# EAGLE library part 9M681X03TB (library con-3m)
CONNECTOR PCMCIA-CompactFlash

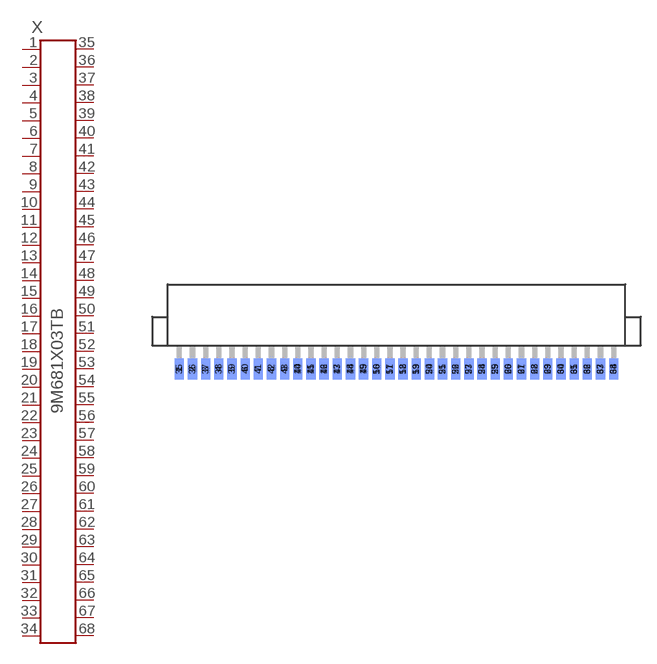
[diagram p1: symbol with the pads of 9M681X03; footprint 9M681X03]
Designator prefix X

## 9M681X03TB (OC_FARNELL: unknown; OC_NEWARK: unknown)  [9M681X03]
1  1  pas
2  2  pas
3  3  pas
4  4  pas
5  5  pas
6  6  pas
7  7  pas
8  8  pas
9  9  pas
10  10  pas
11  11  pas
12  12  pas
13  13  pas
14  14  pas
15  15  pas
16  16  pas
17  17  pas
18  18  pas
19  19  pas
20  20  pas
21  21  pas
22  22  pas
23  23  pas
24  24  pas
25  25  pas
26  26  pas
27  27  pas
28  28  pas
29  29  pas
30  30  pas
31  31  pas
32  32  pas
33  33  pas
34  34  pas
35  35  pas
36  36  pas
37  37  pas
38  38  pas
39  39  pas
40  40  pas
41  41  pas
42  42  pas
43  43  pas
44  44  pas
45  45  pas
46  46  pas
47  47  pas
48  48  pas
49  49  pas
50  50  pas
51  51  pas
52  52  pas
53  53  pas
54  54  pas
55  55  pas
56  56  pas
57  57  pas
58  58  pas
59  59  pas
60  60  pas
61  61  pas
62  62  pas
63  63  pas
64  64  pas
65  65  pas
66  66  pas
67  67  pas
68  68  pas

## Footprint 9M681X03 (pad centres in mm)
CONNECTOR PCMCIA-CompactFlash
smd 0.89 x 2.03: 1 -20.955,-3.29; 2 -19.685,-3.29; 3 -18.415,-3.29; 4 -17.145,-3.29; 5 -15.875,-3.29; 6 -14.605,-3.29; 7 -13.335,-3.29; 8 -12.065,-3.29; 9 -10.795,-3.29; 10 -9.525,-3.29; 11 -8.255,-3.29; 12 -6.985,-3.29; 13 -5.715,-3.29; 14 -4.445,-3.29; 15 -3.175,-3.29; 16 -1.905,-3.29; 17 -0.635,-3.29; 18 0.635,-3.29; 19 1.905,-3.29; 20 3.175,-3.29; 21 4.445,-3.29; 22 5.715,-3.29; 23 6.985,-3.29; 24 8.255,-3.29; 25 9.525,-3.29; 26 10.795,-3.29; 27 12.065,-3.29; 28 13.335,-3.29; 29 14.605,-3.29; 30 15.875,-3.29; 31 17.145,-3.29; 32 18.415,-3.29; 33 19.685,-3.29; 34 20.955,-3.29
smd 0.89 x 2.03 bottom: 35 -20.955,-3.29; 36 -19.685,-3.29; 37 -18.415,-3.29; 38 -17.145,-3.29; 39 -15.875,-3.29; 40 -14.605,-3.29; 41 -13.335,-3.29; 42 -12.065,-3.29; 43 -10.795,-3.29; 44 -9.525,-3.29; 45 -8.255,-3.29; 46 -6.985,-3.29; 47 -5.715,-3.29; 48 -4.445,-3.29; 49 -3.175,-3.29; 50 -1.905,-3.29; 51 -0.635,-3.29; 52 0.635,-3.29; 53 1.905,-3.29; 54 3.175,-3.29; 55 4.445,-3.29; 56 5.715,-3.29; 57 6.985,-3.29; 58 8.255,-3.29; 59 9.525,-3.29; 60 10.795,-3.29; 61 12.065,-3.29; 62 13.335,-3.29; 63 14.605,-3.29; 64 15.875,-3.29; 65 17.145,-3.29; 66 18.415,-3.29; 67 19.685,-3.29; 68 20.955,-3.29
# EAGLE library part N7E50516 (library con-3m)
CONNECTOR PCMCIA-CompactFlash

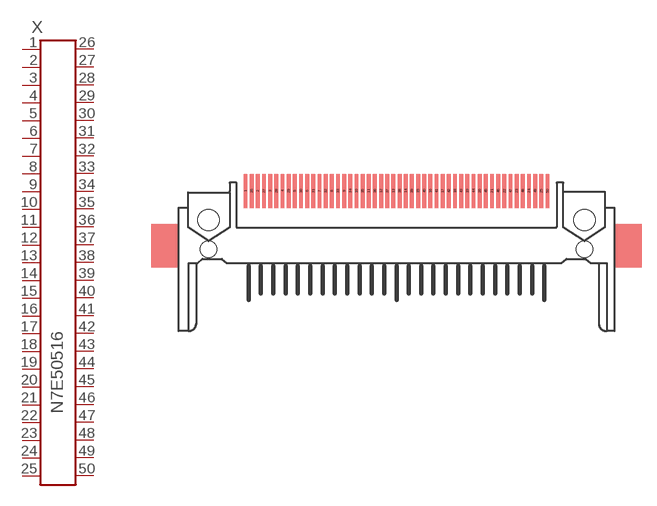
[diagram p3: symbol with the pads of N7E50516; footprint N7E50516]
Designator prefix X

## N7E50516 (OC_FARNELL: unknown; OC_NEWARK: unknown)  [N7E50516]
1  1  pas
2  2  pas
3  3  pas
4  4  pas
5  5  pas
6  6  pas
7  7  pas
8  8  pas
9  9  pas
10  10  pas
11  11  pas
12  12  pas
13  13  pas
14  14  pas
15  15  pas
16  16  pas
17  17  pas
18  18  pas
19  19  pas
20  20  pas
21  21  pas
22  22  pas
23  23  pas
24  24  pas
25  25  pas
26  26  pas
27  27  pas
28  28  pas
29  29  pas
30  30  pas
31  31  pas
32  32  pas
33  33  pas
34  34  pas
35  35  pas
36  36  pas
37  37  pas
38  38  pas
39  39  pas
40  40  pas
41  41  pas
42  42  pas
43  43  pas
44  44  pas
45  45  pas
46  46  pas
47  47  pas
48  48  pas
49  49  pas
50  50  pas

## Footprint N7E50516 (pad centres in mm)
CONNECTOR PCMCIA-CompactFlash
smd 0.4 x 3.5: 1 -15.557,6.015; 2 -14.287,6.015; 3 -13.018,6.015; 4 -11.748,6.015; 5 -10.477,6.015; 6 -9.207,6.015; 7 -7.938,6.015; 8 -6.668,6.015; 9 -5.397,6.015; 10 -4.128,6.015; 11 -2.857,6.015; 12 -1.587,6.015; 13 -0.318,6.015; 14 0.953,6.015; 15 2.223,6.015; 16 3.493,6.015; 17 4.763,6.015; 18 6.032,6.015; 19 7.303,6.015; 20 8.572,6.015; 21 9.842,6.015; 22 11.113,6.015; 23 12.383,6.015; 24 13.652,6.015; 25 14.922,6.015; 26 -14.922,6.015; 27 -13.652,6.015; 28 -12.383,6.015; 29 -11.113,6.015; 30 -9.842,6.015; 31 -8.572,6.015; 32 -7.303,6.015; 33 -6.032,6.015; 34 -4.763,6.015; 35 -3.493,6.015; 36 -2.223,6.015; 37 -0.953,6.015; 38 0.318,6.015; 39 1.587,6.015; 40 2.857,6.015; 41 4.128,6.015; 42 5.397,6.015; 43 6.668,6.015; 44 7.938,6.015; 45 9.207,6.015; 46 10.477,6.015; 47 11.748,6.015; 48 13.018,6.015; 49 14.287,6.015; 50 15.557,6.015
hole 1.7 at -19.37,0
hole 1.7 at 19.37,0
hole 2.2 at -19.37,3
hole 2.2 at 19.37,3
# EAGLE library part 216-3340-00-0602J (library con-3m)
Zero Insertion Force Socked Source: http://www.3M.com/ehpd

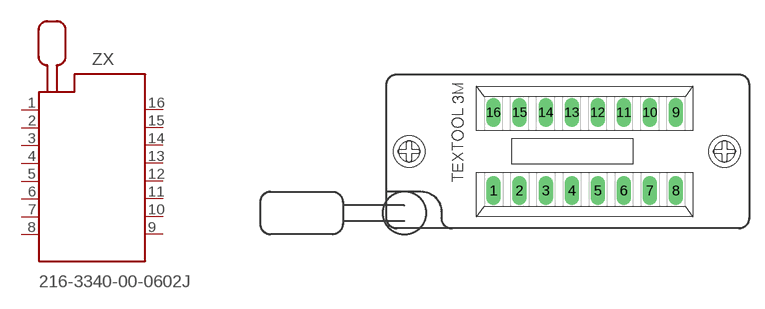
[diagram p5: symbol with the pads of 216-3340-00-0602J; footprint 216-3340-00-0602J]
Designator prefix ZX

## 216-3340-00-0602J (MF: 3M; MPN: 216-3340-00-0602J; OC_FARNELL: 1674399; OC_NEWARK: 85K7797)  [216-3340-00-0602J]
1  1  pas
2  2  pas
3  3  pas
4  4  pas
5  5  pas
6  6  pas
7  7  pas
8  8  pas
9  9  pas
10  10  pas
11  11  pas
12  12  pas
13  13  pas
14  14  pas
15  15  pas
16  16  pas

## Footprint 216-3340-00-0602J (pad centres in mm)
3M TEXTOOL 16 pol. DIP Lever actuated zero insertion force mechanism Hersteller: 3M TEXTOOL Herstellerbez.: 216-3340-00-0602J Farnell Best.-Nr.: 4665430 Source: http://www.3M.com/ehpd
drill 0.9 long: 1 -8.89,-3.81; 2 -6.35,-3.81; 3 -3.81,-3.81; 4 -1.27,-3.81; 5 1.27,-3.81; 6 3.81,-3.81; 7 6.35,-3.81; 8 8.89,-3.81; 9 8.89,3.81; 10 6.35,3.81; 11 3.81,3.81; 12 1.27,3.81; 13 -1.27,3.81; 14 -3.81,3.81; 15 -6.35,3.81; 16 -8.89,3.81
hole 2 at 13.62,0
hole 2 at -17.12,0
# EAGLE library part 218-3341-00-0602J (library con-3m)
Zero Insertion Force Socked Source: http://www.3M.com/ehpd

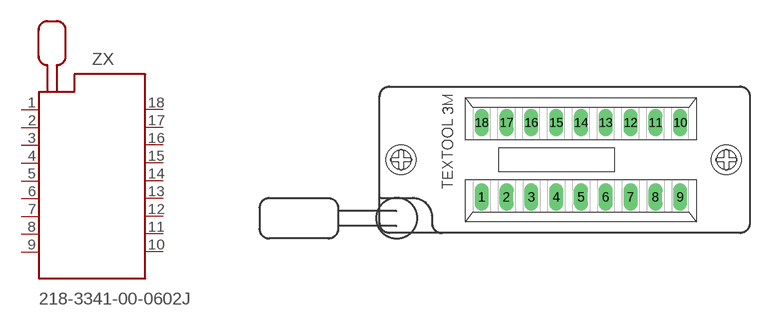
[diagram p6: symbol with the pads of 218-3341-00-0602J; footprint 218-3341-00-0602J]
Designator prefix ZX

## 218-3341-00-0602J (MF: 3M; MPN: 218-3341-00-0602J; OC_FARNELL: 9897461; OC_NEWARK: 85K7802)  [218-3341-00-0602J]
1  1  pas
2  2  pas
3  3  pas
4  4  pas
5  5  pas
6  6  pas
7  7  pas
8  8  pas
9  9  pas
10  10  pas
11  11  pas
12  12  pas
13  13  pas
14  14  pas
15  15  pas
16  16  pas
17  17  pas
18  18  pas

## Footprint 218-3341-00-0602J (pad centres in mm)
3M TEXTOOL 18 pol. DIP Lever actuated zero insertion force mechanism Hersteller: 3M TEXTOOL Herstellerbez.: 218-3341-00-0602J Farnell Best.-Nr.: 4665442 Source: http://www.3M.com/ehpd
drill 0.9 long: 1 -10.16,-3.81; 2 -7.62,-3.81; 3 -5.08,-3.81; 4 -2.54,-3.81; 5 0,-3.81; 6 2.54,-3.81; 7 5.08,-3.81; 8 7.62,-3.81; 9 10.16,-3.81; 10 10.16,3.81; 11 7.62,3.81; 12 5.08,3.81; 13 2.54,3.81; 14 0,3.81; 15 -2.54,3.81; 16 -5.08,3.81; 17 -7.62,3.81; 18 -10.16,3.81
hole 2 at 14.89,0
hole 2 at -18.39,0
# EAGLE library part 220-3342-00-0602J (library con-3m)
Zero Insertion Force Socked Source: http://www.3M.com/ehpd

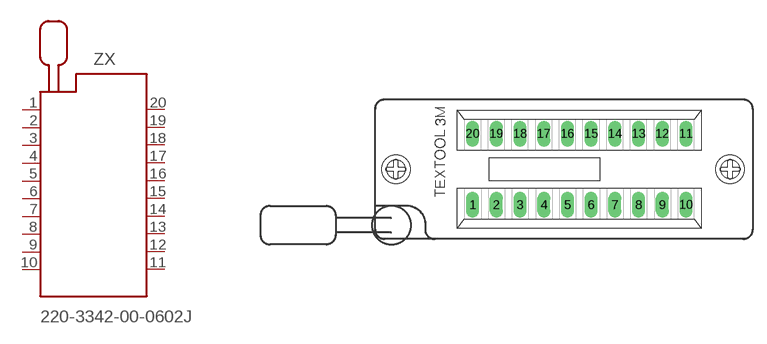
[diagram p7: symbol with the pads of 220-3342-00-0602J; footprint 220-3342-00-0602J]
Designator prefix ZX

## 220-3342-00-0602J (MF: 3M; MPN: 220-3342-00-0602J; OC_FARNELL: 9897445; OC_NEWARK: 85K7807)  [220-3342-00-0602J]
1  1  pas
2  2  pas
3  3  pas
4  4  pas
5  5  pas
6  6  pas
7  7  pas
8  8  pas
9  9  pas
10  10  pas
11  11  pas
12  12  pas
13  13  pas
14  14  pas
15  15  pas
16  16  pas
17  17  pas
18  18  pas
19  19  pas
20  20  pas

## Footprint 220-3342-00-0602J (pad centres in mm)
3M TEXTOOL 20 pol. DIP Lever actuated zero insertion force mechanism Hersteller: 3M TEXTOOL Herstellerbez.: 220-3342-00-0602J Farnell Best.-Nr.: 4677365 Source: http://www.3M.com/ehpd
drill 0.9 long: 1 -11.43,-3.81; 2 -8.89,-3.81; 3 -6.35,-3.81; 4 -3.81,-3.81; 5 -1.27,-3.81; 6 1.27,-3.81; 7 3.81,-3.81; 8 6.35,-3.81; 9 8.89,-3.81; 10 11.43,-3.81; 11 11.43,3.81; 12 8.89,3.81; 13 6.35,3.81; 14 3.81,3.81; 15 1.27,3.81; 16 -1.27,3.81; 17 -3.81,3.81; 18 -6.35,3.81; 19 -8.89,3.81; 20 -11.43,3.81
hole 2 at 16.16,0
hole 2 at -19.66,0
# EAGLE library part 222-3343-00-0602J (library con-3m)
Zero Insertion Force Socked Source: http://www.3M.com/ehpd

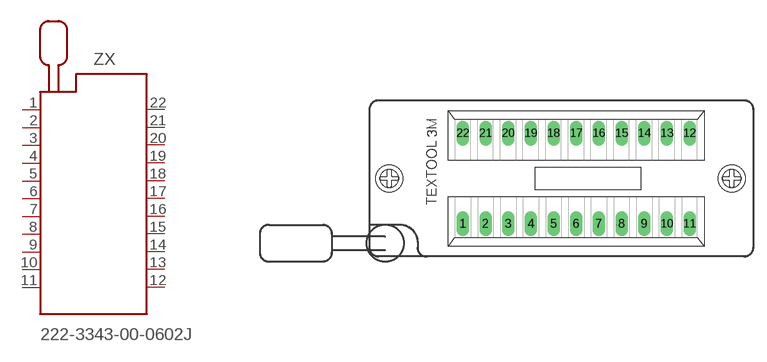
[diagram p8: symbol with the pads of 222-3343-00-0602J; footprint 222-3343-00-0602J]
Designator prefix ZX

## 222-3343-00-0602J (MF: 3M; MPN: 222-3343-00-0602J; OC_FARNELL: unknown; OC_NEWARK: 85K7811)  [222-3343-00-0602J]
1  1  pas
2  2  pas
3  3  pas
4  4  pas
5  5  pas
6  6  pas
7  7  pas
8  8  pas
9  9  pas
10  10  pas
11  11  pas
12  12  pas
13  13  pas
14  14  pas
15  15  pas
16  16  pas
17  17  pas
18  18  pas
19  19  pas
20  20  pas
21  21  pas
22  22  pas

## Footprint 222-3343-00-0602J (pad centres in mm)
3M TEXTOOL 22 pol. DIP Lever actuated zero insertion force mechanism Hersteller: 3M TEXTOOL Herstellerbez.: 222-3343-00-0602J Source: http://www.3M.com/ehpd
drill 0.9 long: 1 -12.7,-5.08; 2 -10.16,-5.08; 3 -7.62,-5.08; 4 -5.08,-5.08; 5 -2.54,-5.08; 6 0,-5.08; 7 2.54,-5.08; 8 5.08,-5.08; 9 7.62,-5.08; 10 10.16,-5.08; 11 12.7,-5.08; 12 12.7,5.08; 13 10.16,5.08; 14 7.62,5.08; 15 5.08,5.08; 16 2.54,5.08; 17 0,5.08; 18 -2.54,5.08; 19 -5.08,5.08; 20 -7.62,5.08; 21 -10.16,5.08; 22 -12.7,5.08
hole 2 at 17.43,0
hole 2 at -20.93,0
